One B-rep face of a CAD part: STEP entity #140.
In plain terms, the planar face has unit normal (-1, 0, 0).
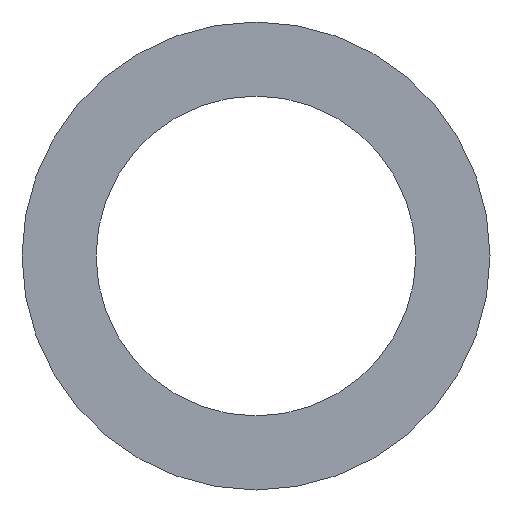
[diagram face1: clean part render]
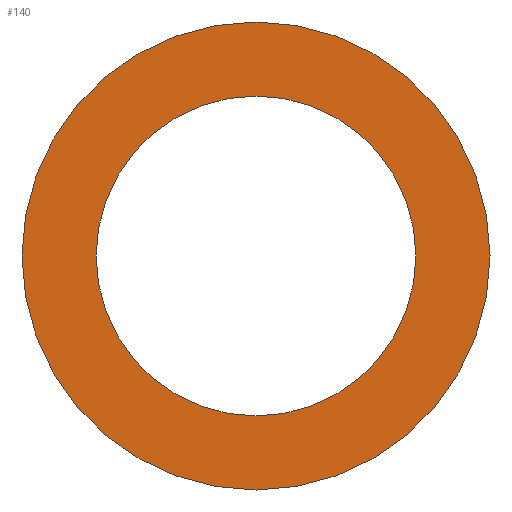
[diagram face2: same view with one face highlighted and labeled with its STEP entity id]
Its self-contained STEP definition (entity closure, numbers rounded to 3 decimals):
#31 = CYLINDRICAL_SURFACE('',#32,6.);
#32 = AXIS2_PLACEMENT_3D('',#33,#34,#35);
#33 = CARTESIAN_POINT('',(83.6,0.,0.));
#34 = DIRECTION('',(1.,0.,0.));
#35 = DIRECTION('',(-0.,0.,1.));
#56 = VERTEX_POINT('',#57);
#57 = CARTESIAN_POINT('',(83.6,0.,6.));
#78 = EDGE_CURVE('',#56,#56,#79,.T.);
#79 = SURFACE_CURVE('',#80,(#85,#92),.PCURVE_S1.);
#80 = CIRCLE('',#81,6.);
#81 = AXIS2_PLACEMENT_3D('',#82,#83,#84);
#82 = CARTESIAN_POINT('',(83.6,0.,0.));
#83 = DIRECTION('',(1.,0.,0.));
#84 = DIRECTION('',(-0.,0.,1.));
#85 = PCURVE('',#31,#86);
#86 = DEFINITIONAL_REPRESENTATION('',(#87),#91);
#87 = LINE('',#88,#89);
#88 = CARTESIAN_POINT('',(0.,0.));
#89 = VECTOR('',#90,1.);
#90 = DIRECTION('',(1.,0.));
#91 = ( GEOMETRIC_REPRESENTATION_CONTEXT(2) 
PARAMETRIC_REPRESENTATION_CONTEXT() REPRESENTATION_CONTEXT('2D SPACE',''
  ) );
#92 = PCURVE('',#93,#98);
#93 = PLANE('',#94);
#94 = AXIS2_PLACEMENT_3D('',#95,#96,#97);
#95 = CARTESIAN_POINT('',(83.6,0.,0.));
#96 = DIRECTION('',(1.,0.,0.));
#97 = DIRECTION('',(-0.,0.,1.));
#98 = DEFINITIONAL_REPRESENTATION('',(#99),#103);
#99 = CIRCLE('',#100,6.);
#100 = AXIS2_PLACEMENT_2D('',#101,#102);
#101 = CARTESIAN_POINT('',(0.,0.));
#102 = DIRECTION('',(1.,0.));
#103 = ( GEOMETRIC_REPRESENTATION_CONTEXT(2) 
PARAMETRIC_REPRESENTATION_CONTEXT() REPRESENTATION_CONTEXT('2D SPACE',''
  ) );
#129 = CYLINDRICAL_SURFACE('',#130,4.1);
#130 = AXIS2_PLACEMENT_3D('',#131,#132,#133);
#131 = CARTESIAN_POINT('',(83.6,0.,0.));
#132 = DIRECTION('',(1.,0.,0.));
#133 = DIRECTION('',(-0.,0.,1.));
#140 = ADVANCED_FACE('',(#141,#144),#93,.F.);
#141 = FACE_BOUND('',#142,.F.);
#142 = EDGE_LOOP('',(#143));
#143 = ORIENTED_EDGE('',*,*,#78,.T.);
#144 = FACE_BOUND('',#145,.F.);
#145 = EDGE_LOOP('',(#146));
#146 = ORIENTED_EDGE('',*,*,#147,.F.);
#147 = EDGE_CURVE('',#148,#148,#150,.T.);
#148 = VERTEX_POINT('',#149);
#149 = CARTESIAN_POINT('',(83.6,0.,4.1));
#150 = SURFACE_CURVE('',#151,(#156,#163),.PCURVE_S1.);
#151 = CIRCLE('',#152,4.1);
#152 = AXIS2_PLACEMENT_3D('',#153,#154,#155);
#153 = CARTESIAN_POINT('',(83.6,0.,0.));
#154 = DIRECTION('',(1.,0.,0.));
#155 = DIRECTION('',(-0.,0.,1.));
#156 = PCURVE('',#93,#157);
#157 = DEFINITIONAL_REPRESENTATION('',(#158),#162);
#158 = CIRCLE('',#159,4.1);
#159 = AXIS2_PLACEMENT_2D('',#160,#161);
#160 = CARTESIAN_POINT('',(0.,0.));
#161 = DIRECTION('',(1.,0.));
#162 = ( GEOMETRIC_REPRESENTATION_CONTEXT(2) 
PARAMETRIC_REPRESENTATION_CONTEXT() REPRESENTATION_CONTEXT('2D SPACE',''
  ) );
#163 = PCURVE('',#129,#164);
#164 = DEFINITIONAL_REPRESENTATION('',(#165),#169);
#165 = LINE('',#166,#167);
#166 = CARTESIAN_POINT('',(0.,0.));
#167 = VECTOR('',#168,1.);
#168 = DIRECTION('',(1.,0.));
#169 = ( GEOMETRIC_REPRESENTATION_CONTEXT(2) 
PARAMETRIC_REPRESENTATION_CONTEXT() REPRESENTATION_CONTEXT('2D SPACE',''
  ) );
